! (c) 2009  Infineon Technologies AG, Munich
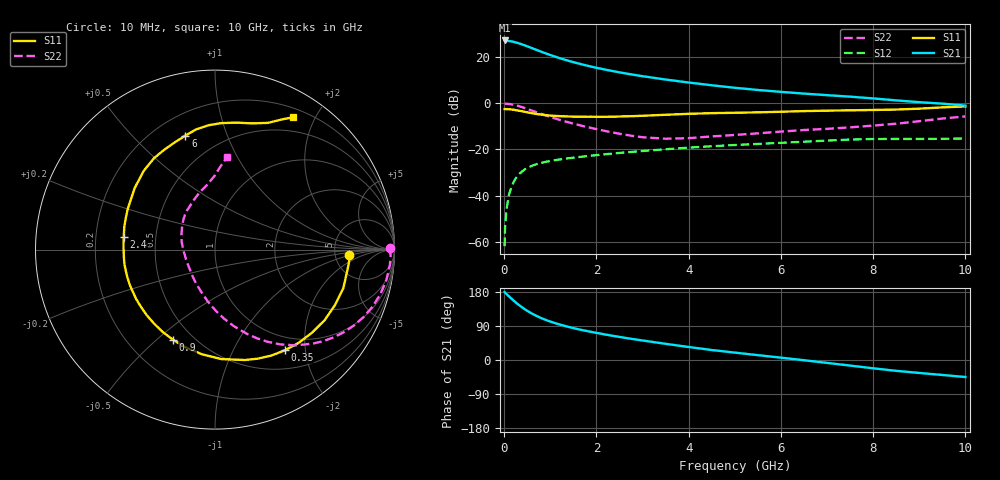
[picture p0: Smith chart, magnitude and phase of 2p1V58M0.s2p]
! Infineon Technologies  Discrete & RF Semiconductors
! BFP420
! VCE =  1.5 V,  IC =  8.0 mA
! Common Emitter S-Parameters:  Nov 2009
# GHz  S  MA  R  50
!  f  S11  S21  S12  S22
! GHz  MAG  ANG  MAG  ANG  MAG  ANG  MAG  ANG
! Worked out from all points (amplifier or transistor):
!   46 points, 10 MHz to 10 GHz, reference 50 ohm
!   highest |S21| = 27.3 dB at 10 MHz (marker M1)
!   |S21| within 3 dB of that: start of sweep to 561.1 MHz
!   unconditionally stable (mu >= 1): 2.518 GHz to end of sweep
!   at 300 MHz: K = 0.15, MSG = 28.7 dB, |S12| = -31.3 dB
!   at 1.7 GHz: K = 0.76, MSG = 20.0 dB, |S12| = -23.1 dB
!   at 10 GHz: K = 1.09, MAG = 5.3 dB, |S12| = -15.3 dB
!   lowest NFmin = 0.79 dB at 900 MHz
!   S11 on the Smith chart (normalised r, x): 10 MHz: 6.87, -0.90; 350 MHz: 0.78, -1.63; 900 MHz: 0.39, -0.57; 2.4 GHz: 0.32, +0.06; 6 GHz: 0.32, +0.72; 10 GHz: 0.31, +1.71
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0.01  0.7497 -2.2  23.06 179.3  0.0008 96.7  0.9732 0.4
0.02  0.7527 -3.5  22.54 177.8  0.002 89.2  0.9791 -1.9
0.05  0.747 -8.2  22.55 174.1  0.0049 86.7  0.9783 -5.0
0.1  0.7466 -16.7  22.46 168.5  0.0099 81.8  0.9696 -10.1
0.2  0.7266 -32.7  21.57 157.4  0.0192 74.5  0.9335 -19.9
0.25  0.7117 -40.5  20.89 152.0  0.0234 70.9  0.9092 -24.4
0.35  0.6826 -55.3  19.53 142.4  0.0308 64.4  0.8509 -32.9
0.45  0.6524 -68.7  18 133.8  0.037 59.0  0.7882 -40.4
0.6  0.6111 -86.6  15.77 122.6  0.0442 52.6  0.6966 -50.0
0.8  0.5693 -106.4  13.19 110.8  0.0511 46.6  0.591 -60.3
0.9  0.5544 -114.9  12.11 105.9  0.0538 44.4  0.5464 -64.7
1.2  0.5273 -136.3  9.571 93.7  0.0606 40.0  0.4389 -76.2
1.4  0.5185 -147.8  8.329 87.2  0.0645 38.0  0.3857 -82.8
1.7  0.5121 -162.2  6.934 78.8  0.0699 35.9  0.3232 -92.0
2.4  0.5137 171.9  4.898 62.9  0.0823 32.0  0.2283 -114.2
3.5  0.564 142.5  3.278 42.7  0.101 25.7  0.1707 -158.7
4.5  0.612 123.8  2.461 26.4  0.1173 18.9  0.1914 166.5
5.5  0.6375 110.8  1.948 12.8  0.1318 12.3  0.2234 145.1
6  0.6566 104.5  1.771 6.2  0.1391 9.0  0.2438 136.1
7  0.6933 93.2  1.502 -7.7  0.1557 1.0  0.2795 120.2
8.5  0.733 73.6  1.158 -28.6  0.1689 -14.3  0.3616 97.3
10  0.8561 59.4  0.891 -44.9  0.1724 -24.3  0.5193 82.5
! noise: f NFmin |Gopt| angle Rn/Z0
0.9  0.79  0.08  30  0.13
1.8  1.14  0.06  171  0.12
2.4  1.24  0.1  160  0.13
3  1.32  0.17  -165  0.12
4  1.46  0.32  -132  0.14
5  1.85  0.39  -110  0.25
6  2.3  0.46  -95  0.37
